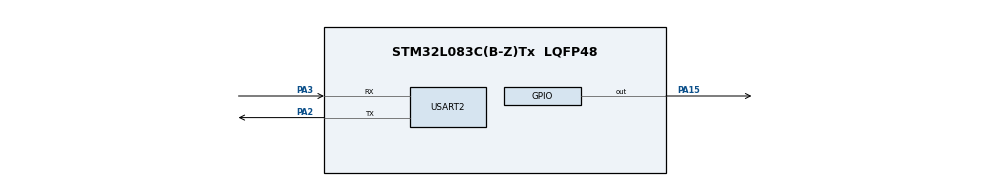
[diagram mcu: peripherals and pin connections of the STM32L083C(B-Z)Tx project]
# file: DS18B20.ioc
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Mcu.Family=STM32L0
Mcu.Name=STM32L083C(B-Z)Tx
Mcu.Package=LQFP48
PA13.Mode=Serial_Wire
PA13.Signal=SYS_SWDIO
PA14.Mode=Serial_Wire
PA14.Signal=SYS_SWCLK
PA15.Signal=GPIO_Output
PA2.Mode=Asynchronous
PA2.Signal=USART2_TX
PA3.Mode=Asynchronous
PA3.Signal=USART2_RX
ProjectManager.HeapSize=0x200
ProjectManager.StackSize=0x400
ProjectManager.TargetToolchain=TrueSTUDIO
RCC.AHBFreq_Value=32000000
RCC.APB1Freq_Value=32000000
RCC.APB1TimFreq_Value=32000000
RCC.APB2Freq_Value=32000000
RCC.APB2TimFreq_Value=32000000
RCC.HCLKFreq_Value=32000000
RCC.HSE_VALUE=8000000
RCC.HSI16_VALUE=16000000
RCC.HSI48_VALUE=48000000
RCC.HSI_VALUE=16000000
RCC.LSE_VALUE=32768
RCC.MSI_VALUE=2097000
RCC.PLLMUL=RCC_PLLMUL_4
RCC.SYSCLKFreq_VALUE=32000000
RCC.SYSCLKSource=RCC_SYSCLKSOURCE_PLLCLK
RCC.VCOOutputFreq_Value=64000000
TIM2.Period=1000
TIM2.Prescaler=32000
USART2.VirtualMode-Asynchronous=VM_ASYNC
VP_TIM2_VS_ClockSourceINT.Mode=Internal
board=custom

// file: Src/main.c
/* USER CODE BEGIN Header */
/**
  ******************************************************************************
  * @file           : main.c
  * @brief          : Main program body
  ******************************************************************************
  * @attention
  *
  * <h2><center>&copy; Copyright (c) 2019 STMicroelectronics.
  * All rights reserved.</center></h2>
  *
  * This software component is licensed by ST under BSD 3-Clause license,
  * the "License"; You may not use this file except in compliance with the
  * License. You may obtain a copy of the License at:
  *                        opensource.org/licenses/BSD-3-Clause
  *
  ******************************************************************************
  */
/* USER CODE END Header */

#include "main.h"

TIM_HandleTypeDef htim2;

UART_HandleTypeDef huart2;

void SystemClock_Config(void);
void SystemClock_Config_HSI(void);
static void MX_GPIO_Init(void);
static void MX_TIM2_Init(void);
static void MX_USART2_UART_Init(void);

/* USER CODE BEGIN 0 */
GPIO_InitTypeDef GPIO_InitStruct;

void gpio_set_input(void)
{
	GPIO_InitStruct.Pin = GPIO_PIN_15;
	GPIO_InitStruct.Mode = GPIO_MODE_INPUT;
	GPIO_InitStruct.Pull = 	GPIO_PULLUP;
	HAL_GPIO_Init(GPIOA , &GPIO_InitStruct);
}

void gpio_set_output(void)
{
	GPIO_InitStruct.Pin = GPIO_PIN_15;
		GPIO_InitStruct.Mode = GPIO_MODE_OUTPUT_PP;
		GPIO_InitStruct.Pull = 	GPIO_NOPULL;
		GPIO_InitStruct.Speed = GPIO_SPEED_FREQ_LOW;
		HAL_GPIO_Init(GPIOA , &GPIO_InitStruct);
}

uint8_t check = 2,temp_l,temp_h;
uint16_t temp;
float temperature;

void write(uint8_t data)
{
	gpio_set_output();

	for(int i=0 ; i<8 ; i++)
	{
		if((data & (1<<i))!=0)
		{
			gpio_set_output();
			HAL_GPIO_WritePin(GPIOA , GPIO_PIN_15,0);
			delay_us(1);
			gpio_set_input();
			delay_us(60);
		}
		else
		{
			gpio_set_output();
			HAL_GPIO_WritePin(GPIOA , GPIO_PIN_15,0);
			delay_us(60);
			gpio_set_input();
		}
	}
}

uint8_t read(void)
{
	uint8_t value=0;
	gpio_set_input();

	  for(int i=0 ; i<8;i++)
	  {
		  gpio_set_output();
			  HAL_GPIO_WritePin(GPIOA , GPIO_PIN_15,0);
			  delay_us(2);
			  gpio_set_input();

			  if(HAL_GPIO_ReadPin(GPIOA , GPIO_PIN_15))
			  {
				  value |= 1<<i;
			  }
			  delay_us(60);
	  }
	  return value;
}

uint8_t ds18b20_init(void)
{
	gpio_set_output();
	HAL_GPIO_WritePin(GPIOA , GPIO_PIN_15,0);
	delay_us(480);
	gpio_set_input();
	delay_us(80);
	if(!(HAL_GPIO_ReadPin(GPIOA , GPIO_PIN_15)))
	  {
		 delay_us(400);
		  return 0;
	  }
	  else
	  {
		  delay_us(400);
		  return 1;

	  }

}

void delay_us(uint16_t micros)
{
	__HAL_TIM_SET_COUNTER(&htim2 , 0);
	while(__HAL_TIM_GET_COUNTER(&htim2)<micros);
}

void print(char* format , ...)
{
	char str[80];

	va_list args;

	va_start(args , format);
	vsprintf(str,format,args);
	HAL_UART_Transmit(&huart2 , (uint8_t*)str , strlen(str),HAL_MAX_DELAY);

	va_end(args);
}

/* USER CODE END 0 */

int main(void)
{

  /* MCU Configuration--------------------------------------------------------*/

  /* Reset of all peripherals, Initializes the Flash interface and the Systick. */
  HAL_Init();

  /* Configure the system clock */
  SystemClock_Config();
  SystemClock_Config_HSI();

  /* Initialize all configured peripherals */
  MX_GPIO_Init();
  MX_TIM2_Init();
  MX_USART2_UART_Init();
  /* USER CODE BEGIN 2 */
  HAL_TIM_Base_Start(&htim2);
  /* USER CODE END 2 */

  /* Infinite loop */
  /* USER CODE BEGIN WHILE */
  while (1)
  {
//	  print("in main\r\n");
//	  HAL_GPIO_TogglePin(GPIOA , GPIO_PIN_15);
//	  HAL_GPIO_WritePin(GPIOA,GPIO_PIN_15,1);
//	  delay_us(1000000);
//	  HAL_GPIO_WritePin(GPIOA,GPIO_PIN_15,0);
//	  HAL_Delay(500);
    /* USER CODE END WHILE */

    /* USER CODE BEGIN 3 */
	  SystemClock_Config_HSI();
	  check = ds18b20_init ();

		  	  write(0xCC);
		  	  write(0x44);
		  	  HAL_Delay(800);

		  	  ds18b20_init ();
			  write(0xCC);
			  write(0xBE);

			  temp_l = read();
			  temp_h = read();

		  	  temp = (temp_h<<8)|temp_l;
		  	  temperature = (float)temp/16;
		  	  print("%f\r\n",temperature);
		  	SystemClock_Config();

  }
  /* USER CODE END 3 */
}

void SystemClock_Config(void)
{
	  RCC_OscInitTypeDef RCC_OscInitStruct = {0};
	  RCC_ClkInitTypeDef RCC_ClkInitStruct = {0};
	  RCC_PeriphCLKInitTypeDef PeriphClkInit = {0};

	  /** Configure the main internal regulator output voltage
	  */
	  __HAL_PWR_VOLTAGESCALING_CONFIG(PWR_REGULATOR_VOLTAGE_SCALE1);
	  /** Configure LSE Drive Capability
	  */
	  HAL_PWR_EnableBkUpAccess();
	  __HAL_RCC_LSEDRIVE_CONFIG(RCC_LSEDRIVE_LOW);
	  /** Initializes the CPU, AHB and APB busses clocks
	  */
	  RCC_OscInitStruct.OscillatorType = RCC_OSCILLATORTYPE_HSE|RCC_OSCILLATORTYPE_LSE;
	  RCC_OscInitStruct.HSEState = RCC_HSE_ON;
	  RCC_OscInitStruct.LSEState = RCC_LSE_ON;
	  RCC_OscInitStruct.PLL.PLLState = RCC_PLL_NONE;
	  if (HAL_RCC_OscConfig(&RCC_OscInitStruct) != HAL_OK)
	  {
	    Error_Handler();
	  }
	  /** Initializes the CPU, AHB and APB busses clocks
	  */
	  RCC_ClkInitStruct.ClockType = RCC_CLOCKTYPE_HCLK|RCC_CLOCKTYPE_SYSCLK
	                              |RCC_CLOCKTYPE_PCLK1|RCC_CLOCKTYPE_PCLK2;
	  RCC_ClkInitStruct.SYSCLKSource = RCC_SYSCLKSOURCE_HSE;
	  RCC_ClkInitStruct.AHBCLKDivider = RCC_SYSCLK_DIV1;
	  RCC_ClkInitStruct.APB1CLKDivider = RCC_HCLK_DIV1;
	  RCC_ClkInitStruct.APB2CLKDivider = RCC_HCLK_DIV1;

	  if (HAL_RCC_ClockConfig(&RCC_ClkInitStruct, FLASH_LATENCY_0) != HAL_OK)
	  {
	    Error_Handler();
	  }
	  PeriphClkInit.PeriphClockSelection = RCC_PERIPHCLK_USART1|RCC_PERIPHCLK_USART2
	                              |RCC_PERIPHCLK_RTC;
	  PeriphClkInit.Usart1ClockSelection = RCC_USART1CLKSOURCE_PCLK2;
	  PeriphClkInit.Usart2ClockSelection = RCC_USART2CLKSOURCE_PCLK1;
	  PeriphClkInit.RTCClockSelection = RCC_RTCCLKSOURCE_LSE;
	  if (HAL_RCCEx_PeriphCLKConfig(&PeriphClkInit) != HAL_OK)
	  {
	    Error_Handler();
//	    error_handler("\r\n error in PerClkCongf\r\n");
	  }
}
void SystemClock_Config_HSI(void)
{
  RCC_OscInitTypeDef RCC_OscInitStruct = {0};
  RCC_ClkInitTypeDef RCC_ClkInitStruct = {0};
  RCC_PeriphCLKInitTypeDef PeriphClkInit = {0};

  /** Configure the main internal regulator output voltage
  */
  __HAL_PWR_VOLTAGESCALING_CONFIG(PWR_REGULATOR_VOLTAGE_SCALE1);
  /** Initializes the CPU, AHB and APB busses clocks
  */
  RCC_OscInitStruct.OscillatorType = RCC_OSCILLATORTYPE_HSI;
  RCC_OscInitStruct.HSIState = RCC_HSI_ON;
  RCC_OscInitStruct.HSICalibrationValue = RCC_HSICALIBRATION_DEFAULT;
  RCC_OscInitStruct.PLL.PLLState = RCC_PLL_ON;
  RCC_OscInitStruct.PLL.PLLSource = RCC_PLLSOURCE_HSI;
  RCC_OscInitStruct.PLL.PLLMUL = RCC_PLLMUL_4;
  RCC_OscInitStruct.PLL.PLLDIV = RCC_PLLDIV_2;
  if (HAL_RCC_OscConfig(&RCC_OscInitStruct) != HAL_OK)
  {
    Error_Handler();
  }
  /** Initializes the CPU, AHB and APB busses clocks
  */
  RCC_ClkInitStruct.ClockType = RCC_CLOCKTYPE_HCLK|RCC_CLOCKTYPE_SYSCLK
                              |RCC_CLOCKTYPE_PCLK1|RCC_CLOCKTYPE_PCLK2;
  RCC_ClkInitStruct.SYSCLKSource = RCC_SYSCLKSOURCE_PLLCLK;
  RCC_ClkInitStruct.AHBCLKDivider = RCC_SYSCLK_DIV1;
  RCC_ClkInitStruct.APB1CLKDivider = RCC_HCLK_DIV1;
  RCC_ClkInitStruct.APB2CLKDivider = RCC_HCLK_DIV1;

  if (HAL_RCC_ClockConfig(&RCC_ClkInitStruct, FLASH_LATENCY_1) != HAL_OK)
  {
    Error_Handler();
  }
  PeriphClkInit.PeriphClockSelection = RCC_PERIPHCLK_USART2;
  PeriphClkInit.Usart2ClockSelection = RCC_USART2CLKSOURCE_PCLK1;
  if (HAL_RCCEx_PeriphCLKConfig(&PeriphClkInit) != HAL_OK)
  {
    Error_Handler();
  }
}

static void MX_TIM2_Init(void)
{

  TIM_ClockConfigTypeDef sClockSourceConfig = {0};
  TIM_MasterConfigTypeDef sMasterConfig = {0};

  htim2.Instance = TIM2;
  htim2.Init.Prescaler = 32-1;
  htim2.Init.CounterMode = TIM_COUNTERMODE_UP;
  htim2.Init.Period = 0xffff-1;
  htim2.Init.ClockDivision = TIM_CLOCKDIVISION_DIV1;
  htim2.Init.AutoReloadPreload = TIM_AUTORELOAD_PRELOAD_DISABLE;
  if (HAL_TIM_Base_Init(&htim2) != HAL_OK)
  {
    Error_Handler();
  }
  sClockSourceConfig.ClockSource = TIM_CLOCKSOURCE_INTERNAL;
  if (HAL_TIM_ConfigClockSource(&htim2, &sClockSourceConfig) != HAL_OK)
  {
    Error_Handler();
  }
  sMasterConfig.MasterOutputTrigger = TIM_TRGO_RESET;
  sMasterConfig.MasterSlaveMode = TIM_MASTERSLAVEMODE_DISABLE;
  if (HAL_TIMEx_MasterConfigSynchronization(&htim2, &sMasterConfig) != HAL_OK)
  {
    Error_Handler();
  }

}

static void MX_USART2_UART_Init(void)
{

  huart2.Instance = USART2;
  huart2.Init.BaudRate = 115200;
  huart2.Init.WordLength = UART_WORDLENGTH_8B;
  huart2.Init.StopBits = UART_STOPBITS_1;
  huart2.Init.Parity = UART_PARITY_NONE;
  huart2.Init.Mode = UART_MODE_TX_RX;
  huart2.Init.HwFlowCtl = UART_HWCONTROL_NONE;
  huart2.Init.OverSampling = UART_OVERSAMPLING_16;
  huart2.Init.OneBitSampling = UART_ONE_BIT_SAMPLE_DISABLE;
  huart2.AdvancedInit.AdvFeatureInit = UART_ADVFEATURE_NO_INIT;
  if (HAL_UART_Init(&huart2) != HAL_OK)
  {
    Error_Handler();
  }

}

static void MX_GPIO_Init(void)
{
  GPIO_InitTypeDef GPIO_InitStruct = {0};

  /* GPIO Ports Clock Enable */
  __HAL_RCC_GPIOA_CLK_ENABLE();

  /*Configure GPIO pin Output Level */
  HAL_GPIO_WritePin(GPIOA, GPIO_PIN_15, GPIO_PIN_RESET);

  /*Configure GPIO pin : PA15 */
  GPIO_InitStruct.Pin = GPIO_PIN_15;
  GPIO_InitStruct.Mode = GPIO_MODE_OUTPUT_PP;
  GPIO_InitStruct.Pull = GPIO_NOPULL;
  GPIO_InitStruct.Speed = GPIO_SPEED_FREQ_LOW;
  HAL_GPIO_Init(GPIOA, &GPIO_InitStruct);

}

/* USER CODE BEGIN 4 */
void HAL_TIM_PeriodElapsedCallback(TIM_HandleTypeDef *htim)
{
  /* Prevent unused argument(s) compilation warning */
//  UNUSED(htim);
	print("In Interrupt\r\n");

  /* NOTE : This function should not be modified, when the callback is needed,
            the HAL_TIM_PeriodElapsedCallback could be implemented in the user file
   */
}
/* USER CODE END 4 */

void Error_Handler(void)
{
}

/************************ (C) COPYRIGHT STMicroelectronics *****END OF FILE****/
